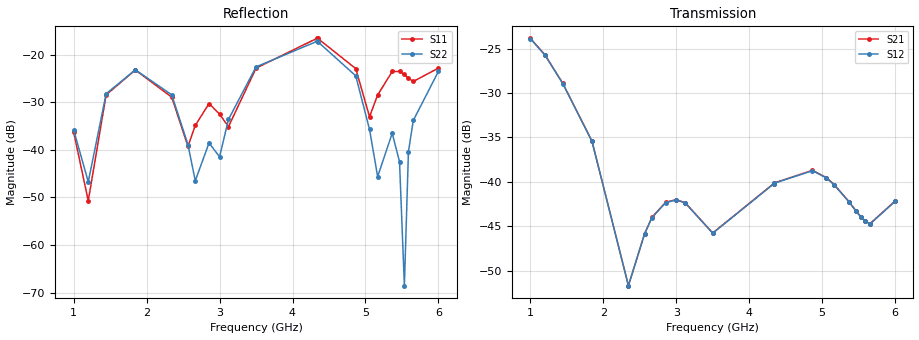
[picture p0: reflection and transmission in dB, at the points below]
!Agilent Technologies,E8364B,MY43040528,A.07.50.67
!Agilent E8364B: A.07.50.67
!Date: Sunday, March 01, 2026 22:09:29
!Correction: S11(Full 2 Port(1,2))
!S21(Full 2 Port(1,2))
!S12(Full 2 Port(1,2))
!S22(Full 2 Port(1,2))
!S2P File: Measurements: S11, S21, S12, S22:
# Hz S  dB  R 50
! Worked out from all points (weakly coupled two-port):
!   451 points, 1 GHz to 6 GHz, reference 50 ohm
!   highest |S21| = -23.84 dB at 1 GHz (marker M1); lowest = -51.7 dB at 2.344 GHz (marker M2)
!   lowest |S11| = -50.7 dB at 1.2 GHz (marker M3), VSWR 1.01, Z = 50.1 - j0.256 ohm
!   |S11| at or under -10 dB: start of sweep to end of sweep
!   |S22| runs from -68.5 to -17.2 dB; largest |S21 - S12| = 0.00025
!   S11 on the Smith chart (normalised r, x): 1 GHz: 1.03, +0.01; 4.333 GHz: 1.23, -0.24; 6 GHz: 0.98, -0.14
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1e9  -36.30 16.0  -23.84 155.1  -23.87 155.1  -35.84 -44.4
1.2e9  -50.70 -61.1  -25.69 41.2  -25.73 41.2  -46.72 -137.7
1.444444e9  -28.46 171.6  -28.91 -94.9  -28.93 -94.9  -28.24 107.1
1.844444e9  -23.23 83.2  -35.40 51.8  -35.44 51.9  -23.19 -5.4
2.344444e9  -28.94 12.9  -51.71 -147.9  -51.69 -148.1  -28.45 -119.9
2.566667e9  -39.28 34.5  -45.83 152.6  -45.87 152.7  -38.91 166.1
2.666667e9  -34.87 70.9  -44.01 104.4  -44.04 104.3  -46.50 43.6
2.855556e9  -30.28 51.4  -42.30 7.4  -42.35 7.4  -38.55 -53.0
3e9  -32.51 36.5  -42.02 -68.4  -42.05 -68.4  -41.46 -37.6
3.122222e9  -35.13 68.8  -42.35 -132.1  -42.38 -132.1  -33.60 -18.3
3.5e9  -22.84 55.0  -45.77 47.5  -45.80 47.6  -22.58 -105.2
4.333333e9  -16.60 -39.2  -40.22 30.5  -40.25 30.5  -17.23 105.8
4.344444e9  -16.59 -40.9  -40.13 24.5  -40.17 24.5  -17.26 103.3
4.866667e9  -22.94 -125.7  -38.71 91.8  -38.75 91.9  -24.46 -25.2
5.055556e9  -33.06 -103.3  -39.52 -19.7  -39.55 -19.6  -35.71 -89.6
5.166667e9  -28.49 -61.6  -40.32 -86.6  -40.36 -86.6  -45.62 115.1
5.366667e9  -23.54 -82.1  -42.23 148.2  -42.26 148.2  -36.51 19.2
5.466667e9  -23.54 -95.6  -43.30 81.6  -43.34 81.6  -42.50 -19.7
5.533333e9  -24.15 -101.0  -43.97 35.1  -44.01 35.2  -68.53 65.3
5.588889e9  -24.96 -103.7  -44.41 -4.8  -44.45 -4.8  -40.39 121.1
5.655556e9  -25.64 -102.7  -44.73 -53.9  -44.76 -53.8  -33.82 103.1
6e9  -22.84 -94.8  -42.17 60.8  -42.21 60.9  -23.52 3.0
